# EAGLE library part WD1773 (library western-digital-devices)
WD1773 Floppy Disk Formatter/Controller

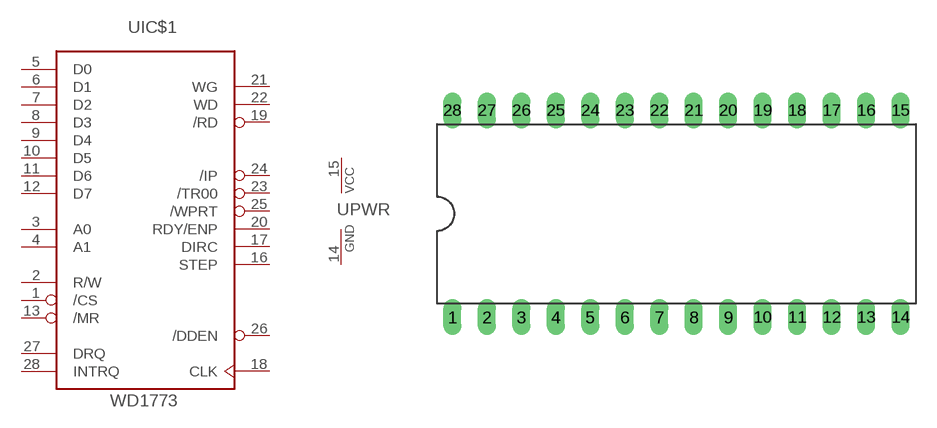
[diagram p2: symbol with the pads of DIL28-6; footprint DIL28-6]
Designator prefix -; gates IC$1=WD1773 PWR=PWRN

## WD1773  [DIL28-6]
1  IC$1:/CS  in
2  IC$1:R/W  in
3  IC$1:A0  in
4  IC$1:A1  in
5  IC$1:D0
6  IC$1:D1
7  IC$1:D2
8  IC$1:D3
9  IC$1:D4
10  IC$1:D5
11  IC$1:D6
12  IC$1:D7
13  IC$1:/MR  in
14  PWR:GND  pwr
15  PWR:VCC  pwr
16  IC$1:STEP  out
17  IC$1:DIRC  out
18  IC$1:CLK  in
19  IC$1:/RD  in
20  IC$1:RDY/ENP  in
21  IC$1:WG  out
22  IC$1:WD  out
23  IC$1:/TR00  in
24  IC$1:/IP  in
25  IC$1:/WPRT  in
26  IC$1:/DDEN  in
27  IC$1:DRQ  out
28  IC$1:INTRQ  out

## Footprint DIL28-6 (pad centres in mm)
drill 0.813 long: 1 -16.51,-7.62; 2 -13.97,-7.62; 3 -11.43,-7.62; 4 -8.89,-7.62; 5 -6.35,-7.62; 6 -3.81,-7.62; 7 -1.27,-7.62; 8 1.27,-7.62; 9 3.81,-7.62; 10 6.35,-7.62; 11 8.89,-7.62; 12 11.43,-7.62; 13 13.97,-7.62; 14 16.51,-7.62; 15 16.51,7.62; 16 13.97,7.62; 17 11.43,7.62; 18 8.89,7.62; 19 6.35,7.62; 20 3.81,7.62; 21 1.27,7.62; 22 -1.27,7.62; 23 -3.81,7.62; 24 -6.35,7.62; 25 -8.89,7.62; 26 -11.43,7.62; 27 -13.97,7.62; 28 -16.51,7.62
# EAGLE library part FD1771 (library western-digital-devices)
FD1771 Floppy Disk Formatter/Controller

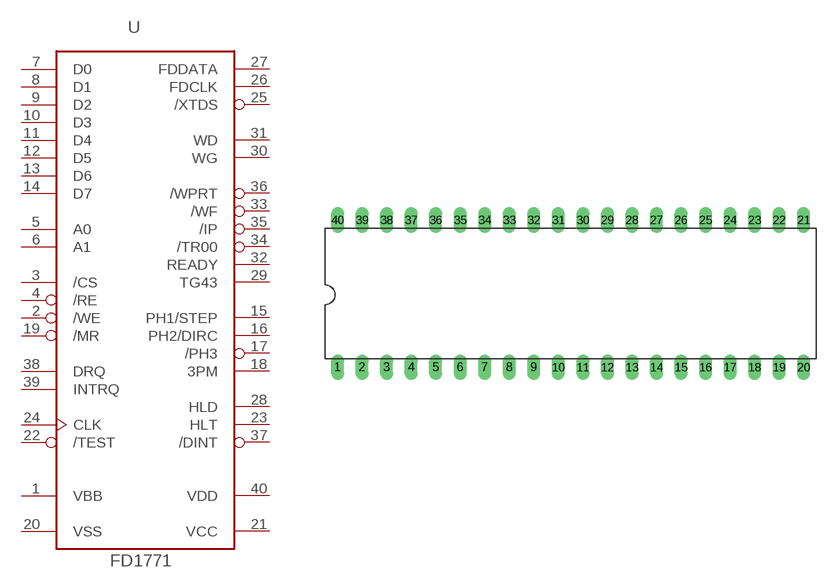
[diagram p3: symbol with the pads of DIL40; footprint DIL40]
Designator prefix -

## FD1771  [DIL40]
1  VBB  pwr
2  /WE  in
3  /CS  in
4  /RE  in
5  A0  in
6  A1  in
7  D0
8  D1
9  D2
10  D3
11  D4
12  D5
13  D6
14  D7
15  PH1/STEP  out
16  PH2/DIRC  out
17  /PH3  out
18  3PM  in
19  /MR  in
20  VSS  pwr
21  VCC  pwr
22  /TEST  in
23  HLT  in
24  CLK  in
25  /XTDS  in
26  FDCLK  in
27  FDDATA  in
28  HLD  out
29  TG43  out
30  WG  out
31  WD  out
32  READY  in
33  /WF  in
34  /TR00  in
35  /IP  in
36  /WPRT  in
37  /DINT  in
38  DRQ  out
39  INTRQ  out
40  VDD  pwr

## Footprint DIL40 (pad centres in mm)
drill 0.813 long: 1 -24.13,-7.62; 2 -21.59,-7.62; 3 -19.05,-7.62; 4 -16.51,-7.62; 5 -13.97,-7.62; 6 -11.43,-7.62; 7 -8.89,-7.62; 8 -6.35,-7.62; 9 -3.81,-7.62; 10 -1.27,-7.62; 11 1.27,-7.62; 12 3.81,-7.62; 13 6.35,-7.62; 14 8.89,-7.62; 15 11.43,-7.62; 16 13.97,-7.62; 17 16.51,-7.62; 18 19.05,-7.62; 19 21.59,-7.62; 20 24.13,-7.62; 21 24.13,7.62; 22 21.59,7.62; 23 19.05,7.62; 24 16.51,7.62; 25 13.97,7.62; 26 11.43,7.62; 27 8.89,7.62; 28 6.35,7.62; 29 3.81,7.62; 30 1.27,7.62; 31 -1.27,7.62; 32 -3.81,7.62; 33 -6.35,7.62; 34 -8.89,7.62; 35 -11.43,7.62; 36 -13.97,7.62; 37 -16.51,7.62; 38 -19.05,7.62; 39 -21.59,7.62; 40 -24.13,7.62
